# Generated by FakeRAM 2.0
VERSION 5.7 ;
BUSBITCHARS "[]" ;
PROPERTYDEFINITIONS
  MACRO width INTEGER ;
  MACRO depth INTEGER ;
  MACRO banks INTEGER ;
END PROPERTYDEFINITIONS
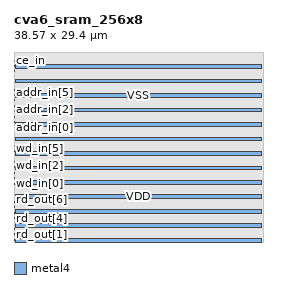
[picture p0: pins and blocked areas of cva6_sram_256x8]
MACRO cva6_sram_256x8
  PROPERTY width 8 ;
  PROPERTY depth 256 ;
  PROPERTY banks 1 ;
  FOREIGN cva6_sram_256x8 0 0 ;
  SYMMETRY X Y R90 ;
  SIZE 38.5700 BY 29.4000 ;
  CLASS BLOCK ;
  PIN rd_out[0]
    DIRECTION OUTPUT ;
    USE SIGNAL ;
    PORT
      LAYER metal4 ;
      RECT 0.00000 0.28000 0.14000 0.42000 ;
    END
  END rd_out[0]
  PIN rd_out[1]
    DIRECTION OUTPUT ;
    USE SIGNAL ;
    PORT
      LAYER metal4 ;
      RECT 0.00000 1.12000 0.14000 1.26000 ;
    END
  END rd_out[1]
  PIN rd_out[2]
    DIRECTION OUTPUT ;
    USE SIGNAL ;
    PORT
      LAYER metal4 ;
      RECT 0.00000 1.96000 0.14000 2.10000 ;
    END
  END rd_out[2]
  PIN rd_out[3]
    DIRECTION OUTPUT ;
    USE SIGNAL ;
    PORT
      LAYER metal4 ;
      RECT 0.00000 2.80000 0.14000 2.94000 ;
    END
  END rd_out[3]
  PIN rd_out[4]
    DIRECTION OUTPUT ;
    USE SIGNAL ;
    PORT
      LAYER metal4 ;
      RECT 0.00000 3.64000 0.14000 3.78000 ;
    END
  END rd_out[4]
  PIN rd_out[5]
    DIRECTION OUTPUT ;
    USE SIGNAL ;
    PORT
      LAYER metal4 ;
      RECT 0.00000 4.48000 0.14000 4.62000 ;
    END
  END rd_out[5]
  PIN rd_out[6]
    DIRECTION OUTPUT ;
    USE SIGNAL ;
    PORT
      LAYER metal4 ;
      RECT 0.00000 5.32000 0.14000 5.46000 ;
    END
  END rd_out[6]
  PIN rd_out[7]
    DIRECTION OUTPUT ;
    USE SIGNAL ;
    PORT
      LAYER metal4 ;
      RECT 0.00000 6.16000 0.14000 6.30000 ;
    END
  END rd_out[7]
  PIN wd_in[0]
    DIRECTION INPUT ;
    USE SIGNAL ;
    PORT
      LAYER metal4 ;
      RECT 0.00000 8.96000 0.14000 9.10000 ;
    END
  END wd_in[0]
  PIN wd_in[1]
    DIRECTION INPUT ;
    USE SIGNAL ;
    PORT
      LAYER metal4 ;
      RECT 0.00000 9.80000 0.14000 9.94000 ;
    END
  END wd_in[1]
  PIN wd_in[2]
    DIRECTION INPUT ;
    USE SIGNAL ;
    PORT
      LAYER metal4 ;
      RECT 0.00000 10.64000 0.14000 10.78000 ;
    END
  END wd_in[2]
  PIN wd_in[3]
    DIRECTION INPUT ;
    USE SIGNAL ;
    PORT
      LAYER metal4 ;
      RECT 0.00000 11.48000 0.14000 11.62000 ;
    END
  END wd_in[3]
  PIN wd_in[4]
    DIRECTION INPUT ;
    USE SIGNAL ;
    PORT
      LAYER metal4 ;
      RECT 0.00000 12.32000 0.14000 12.46000 ;
    END
  END wd_in[4]
  PIN wd_in[5]
    DIRECTION INPUT ;
    USE SIGNAL ;
    PORT
      LAYER metal4 ;
      RECT 0.00000 13.16000 0.14000 13.30000 ;
    END
  END wd_in[5]
  PIN wd_in[6]
    DIRECTION INPUT ;
    USE SIGNAL ;
    PORT
      LAYER metal4 ;
      RECT 0.00000 14.00000 0.14000 14.14000 ;
    END
  END wd_in[6]
  PIN wd_in[7]
    DIRECTION INPUT ;
    USE SIGNAL ;
    PORT
      LAYER metal4 ;
      RECT 0.00000 14.84000 0.14000 14.98000 ;
    END
  END wd_in[7]
  PIN addr_in[0]
    DIRECTION INPUT ;
    USE SIGNAL ;
    PORT
      LAYER metal4 ;
      RECT 0.00000 17.64000 0.14000 17.78000 ;
    END
  END addr_in[0]
  PIN addr_in[1]
    DIRECTION INPUT ;
    USE SIGNAL ;
    PORT
      LAYER metal4 ;
      RECT 0.00000 18.48000 0.14000 18.62000 ;
    END
  END addr_in[1]
  PIN addr_in[2]
    DIRECTION INPUT ;
    USE SIGNAL ;
    PORT
      LAYER metal4 ;
      RECT 0.00000 19.32000 0.14000 19.46000 ;
    END
  END addr_in[2]
  PIN addr_in[3]
    DIRECTION INPUT ;
    USE SIGNAL ;
    PORT
      LAYER metal4 ;
      RECT 0.00000 20.16000 0.14000 20.30000 ;
    END
  END addr_in[3]
  PIN addr_in[4]
    DIRECTION INPUT ;
    USE SIGNAL ;
    PORT
      LAYER metal4 ;
      RECT 0.00000 21.00000 0.14000 21.14000 ;
    END
  END addr_in[4]
  PIN addr_in[5]
    DIRECTION INPUT ;
    USE SIGNAL ;
    PORT
      LAYER metal4 ;
      RECT 0.00000 21.84000 0.14000 21.98000 ;
    END
  END addr_in[5]
  PIN addr_in[6]
    DIRECTION INPUT ;
    USE SIGNAL ;
    PORT
      LAYER metal4 ;
      RECT 0.00000 22.68000 0.14000 22.82000 ;
    END
  END addr_in[6]
  PIN addr_in[7]
    DIRECTION INPUT ;
    USE SIGNAL ;
    PORT
      LAYER metal4 ;
      RECT 0.00000 23.52000 0.14000 23.66000 ;
    END
  END addr_in[7]
  PIN we_in
    DIRECTION INPUT ;
    USE SIGNAL ;
    PORT
      LAYER metal4 ;
      RECT 0.00000 26.32000 0.14000 26.46000 ;
    END
  END we_in
  PIN clk
    DIRECTION INPUT ;
    USE SIGNAL ;
    PORT
      LAYER metal4 ;
      RECT 0.00000 27.16000 0.14000 27.30000 ;
    END
  END clk
  PIN ce_in
    DIRECTION INPUT ;
    USE SIGNAL ;
    PORT
      LAYER metal4 ;
      RECT 0.00000 28.00000 0.14000 28.14000 ;
    END
  END ce_in
  PIN VDD
    DIRECTION INOUT ;
    USE POWER ;
    PORT
      LAYER metal4 ;
      RECT 0.28000 2.24000 38.29000 2.80000 ;
      RECT 0.28000 6.72000 38.29000 7.28000 ;
      RECT 0.28000 11.20000 38.29000 11.76000 ;
      RECT 0.28000 15.68000 38.29000 16.24000 ;
      RECT 0.28000 20.16000 38.29000 20.72000 ;
      RECT 0.28000 24.64000 38.29000 25.20000 ;
    END
  END VDD
  PIN VSS
    DIRECTION INOUT ;
    USE GROUND ;
    PORT
      LAYER metal4 ;
      RECT 0.28000 0.00000 38.29000 0.56000 ;
      RECT 0.28000 4.48000 38.29000 5.04000 ;
      RECT 0.28000 8.96000 38.29000 9.52000 ;
      RECT 0.28000 13.44000 38.29000 14.00000 ;
      RECT 0.28000 17.92000 38.29000 18.48000 ;
      RECT 0.28000 22.40000 38.29000 22.96000 ;
      RECT 0.28000 26.88000 38.29000 27.44000 ;
    END
  END VSS
  OBS
    LAYER metal1 ;
    RECT 0 0 38.57000 29.40000 ;
    LAYER metal2 ;
    RECT 0 0 38.57000 29.40000 ;
    LAYER metal3 ;
    RECT 0 0 38.57000 29.40000 ;
    LAYER metal4 ;
    RECT 0 0 38.57000 29.40000 ;
  END
END cva6_sram_256x8

END LIBRARY
